# LEF file generated by Abstract Generator version 5.5.9 on Apr 28 16:11:38 2004
#
# Contains LEF for all bins.
# Options:   [ ] Antenna
#            [x] Geometry
#            [x] Technology

VERSION 5.7 ;
NAMESCASESENSITIVE ON ;
BUSBITCHARS "[]" ;
DIVIDERCHAR "/" ;

PROPERTYDEFINITIONS
  LAYER LEF57_SPACING STRING ;
  LAYER LEF57_ARRAYSPACING STRING ;
END PROPERTYDEFINITIONS

UNITS
  DATABASE MICRONS 1000 ;
END UNITS

USEMINSPACING OBS OFF ;
USEMINSPACING PIN OFF ;
CLEARANCEMEASURE EUCLIDEAN ;

MANUFACTURINGGRID 0.005 ;

LAYER DIFF
  TYPE MASTERSLICE ;
END DIFF

LAYER PO1
  TYPE MASTERSLICE ;
END PO1

LAYER VTPH
  TYPE IMPLANT ;
  SPACING 0.4  ;
  WIDTH 0.4 ;
END VTPH

LAYER VTNH
  TYPE IMPLANT ;
  SPACING 0.4  ;
  WIDTH 0.4 ;
END VTNH

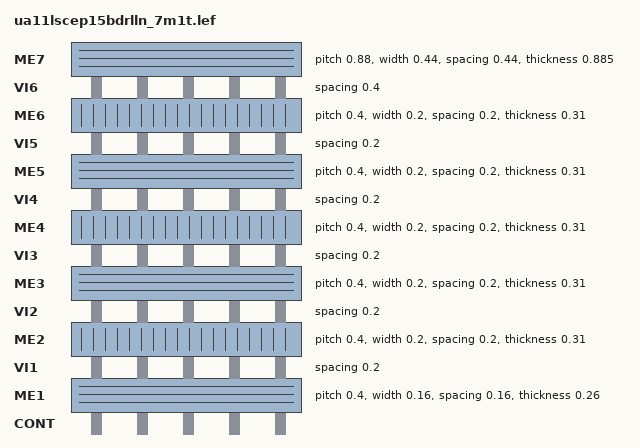
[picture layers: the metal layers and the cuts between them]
LAYER CONT
  TYPE CUT ;
END CONT

LAYER ME1
  TYPE		ROUTING ;
  DIRECTION	HORIZONTAL ;
  PITCH		0.4 ;
  OFFSET        0.2  ;
  WIDTH		0.16 ;
  SPACING	0.16 ;
  SPACING	0.22 RANGE 2.000 5.000  ;
  SPACING	0.26 RANGE 5.005 500  ;
  RESISTANCE	RPERSQ 0.196 ;
  CAPACITANCE	CPERSQDIST 1.7435e-04 ;
  EDGECAPACITANCE 1.0789e-04 ;
  THICKNESS 0.26 ;
  ANTENNASIDEAREARATIO 400 ;
  ANTENNADIFFSIDEAREARATIO PWL ( ( 0 400 ) ( 0.1023 400 ) ( 0.1024 2020 ) ( 100 22000 ) ) ;
  ANTENNACUMDIFFSIDEAREARATIO PWL ( ( 0 400 ) ( 0.1023 400 ) ( 0.1024 2020 ) ( 100 22000 ) ) ;
  AREA	0.1024 ;
  MINENCLOSEDAREA	0.3072 ;
  MINIMUMCUT	2 WIDTH	1.4 WITHIN 0.6 ;
  MINIMUMDENSITY 30 ;
  FILLACTIVESPACING  0.8 ;
END ME1

LAYER VI1
  TYPE	CUT ;
  SPACING    0.2 ;
  SPACING    0.24 ADJACENTCUTS 4 WITHIN 0.24 ;
END VI1

LAYER ME2
  TYPE		ROUTING ;
  DIRECTION	VERTICAL ;
  PITCH		0.4 ;
  OFFSET        0.2 ;  
  WIDTH		0.2 ;
  SPACING	0.2 ;
  SPACING	0.22 RANGE 2.000 5.000  ;
  SPACING	0.26 RANGE 5.005 500  ;
  RESISTANCE	RPERSQ 0.147 ;
  CAPACITANCE	CPERSQDIST 1.6801e-04 ;
  EDGECAPACITANCE 1.0243e-04 ;
  THICKNESS 0.31 ;
  ANTENNASIDEAREARATIO 400 ;
  ANTENNADIFFSIDEAREARATIO PWL ( ( 0 400 ) ( 0.1023 400 ) ( 0.1024 2020 ) ( 100 22000 ) ) ;
  ANTENNACUMDIFFSIDEAREARATIO PWL ( ( 0 400 ) ( 0.1023 400 ) ( 0.1024 2020 ) ( 100 22000 ) ) ;
  AREA	0.1024 ;
  MINENCLOSEDAREA	0.3072 ;
  MINIMUMCUT	2 WIDTH	1.4 WITHIN 0.6 ;
  MINIMUMDENSITY 30 ;
  FILLACTIVESPACING  0.8 ;  
END ME2

LAYER VI2
  TYPE	CUT ;
  SPACING    0.2 ;
  SPACING    0.24 ADJACENTCUTS 4 WITHIN 0.24 ;
END VI2

LAYER ME3
  TYPE		ROUTING ;
  DIRECTION	HORIZONTAL ;
  PITCH		0.4 ;
  OFFSET        0.2  ;  
  WIDTH		0.2 ;
  SPACING	0.2 ;
  SPACING	0.22 RANGE 2.000 5.000  ;
  SPACING	0.26 RANGE 5.005 500  ;
  RESISTANCE	RPERSQ 0.147 ;
  CAPACITANCE	CPERSQDIST 1.4924e-04 ;
  EDGECAPACITANCE 1.025e-04 ;
  THICKNESS 0.31 ;
  ANTENNASIDEAREARATIO 400 ;
  ANTENNADIFFSIDEAREARATIO PWL ( ( 0 400 ) ( 0.1023 400 ) ( 0.1024 2020 ) ( 100 22000 ) ) ;
  ANTENNACUMDIFFSIDEAREARATIO PWL ( ( 0 400 ) ( 0.1023 400 ) ( 0.1024 2020 ) ( 100 22000 ) ) ;
  AREA	0.1024 ;
  MINENCLOSEDAREA	0.3072 ;
  MINIMUMCUT	2 WIDTH	1.4 WITHIN 0.6 ;
  MINIMUMDENSITY 30 ;
  FILLACTIVESPACING  0.8 ;
END ME3

LAYER VI3
  TYPE	CUT ;
  SPACING    0.2 ;
  SPACING    0.24 ADJACENTCUTS 4 WITHIN 0.24 ;
END VI3

LAYER ME4
  TYPE		ROUTING ;
  DIRECTION	VERTICAL ;
  PITCH		0.4 ;
  OFFSET        0.2 ;  
  WIDTH		0.2 ;
  SPACING	0.2 ;
  SPACING	0.22 RANGE 2.000 5.000  ;
  SPACING	0.26 RANGE 5.005 500  ;
  RESISTANCE	RPERSQ 0.147 ;
  CAPACITANCE	CPERSQDIST 1.4924e-04 ;
  EDGECAPACITANCE 1.025e-04 ;
  THICKNESS 0.31 ;
  ANTENNASIDEAREARATIO 400 ;
  ANTENNADIFFSIDEAREARATIO PWL ( ( 0 400 ) ( 0.1023 400 ) ( 0.1024 2020 ) ( 100 22000 ) ) ;
  ANTENNACUMDIFFSIDEAREARATIO PWL ( ( 0 400 ) ( 0.1023 400 ) ( 0.1024 2020 ) ( 100 22000 ) ) ;
  AREA	0.1024 ;
  MINENCLOSEDAREA	0.3072 ;
  MINIMUMCUT	2 WIDTH	1.4 WITHIN 0.6 ;
  MINIMUMDENSITY 30 ;
  FILLACTIVESPACING  0.8 ;
END ME4

LAYER VI4
  TYPE	CUT ;
  SPACING    0.2 ;
  SPACING    0.24 ADJACENTCUTS 4 WITHIN 0.24 ;
END VI4

LAYER ME5
  TYPE		ROUTING ;
  DIRECTION	HORIZONTAL ;
  PITCH		0.4 ;
  OFFSET        0.2  ;
  WIDTH		0.2 ;
  SPACING	0.2 ;
  SPACING	0.22 RANGE 2.000 5.000  ;
  SPACING	0.26 RANGE 5.005 500  ;
  RESISTANCE	RPERSQ 0.147 ;
  CAPACITANCE	CPERSQDIST 1.4848e-04 ;
  EDGECAPACITANCE 1.025e-04 ;
  THICKNESS 0.31 ;
  ANTENNASIDEAREARATIO 400 ;
  ANTENNADIFFSIDEAREARATIO PWL ( ( 0 400 ) ( 0.1023 400 ) ( 0.1024 2020 ) ( 100 22000 ) ) ;
  ANTENNACUMDIFFSIDEAREARATIO PWL ( ( 0 400 ) ( 0.1023 400 ) ( 0.1024 2020 ) ( 100 22000 ) ) ;
  AREA	0.1024 ;
  MINENCLOSEDAREA	0.3072 ;
  MINIMUMCUT	2 WIDTH	1.4 WITHIN 0.6 ;
  MINIMUMDENSITY 30 ;
  FILLACTIVESPACING  0.8 ;  
END ME5

LAYER VI5
  TYPE	CUT ;
  SPACING    0.2 ;
  SPACING    0.24 ADJACENTCUTS 4 WITHIN 0.24 ;
END VI5

LAYER ME6
  TYPE		ROUTING ;
  DIRECTION	VERTICAL ;
  PITCH		0.4 ;
  OFFSET        0.2 ;  
  WIDTH		0.2 ;
  SPACING	0.2 ;
  SPACING	0.22 RANGE 2.000 5.000  ;
  SPACING	0.26 RANGE 5.005 500  ;
  RESISTANCE	RPERSQ 0.147 ;
  CAPACITANCE	CPERSQDIST 1.2056e-04 ;
  EDGECAPACITANCE 1.0259e-04 ;
  THICKNESS 0.31 ;
  ANTENNASIDEAREARATIO 400 ;
  ANTENNADIFFSIDEAREARATIO PWL ( ( 0 400 ) ( 0.1023 400 ) ( 0.1024 2020 ) ( 100 22000 ) ) ;
  ANTENNACUMDIFFSIDEAREARATIO PWL ( ( 0 400 ) ( 0.1023 400 ) ( 0.1024 2020 ) ( 100 22000 ) ) ;
  AREA	0.1024 ;
  MINENCLOSEDAREA	0.3072 ;
  MINIMUMCUT	2 WIDTH	1.4 WITHIN 0.6 ;
  MINIMUMDENSITY 30 ;
  FILLACTIVESPACING  0.8 ;  
END ME6

LAYER VI6
  TYPE	CUT ;
  SPACING    0.4 ;  
  SPACING    0.45 ADJACENTCUTS 4 WITHIN 0.5 ;
END VI6

LAYER ME7
  TYPE		ROUTING ;
  DIRECTION	HORIZONTAL ;
  PITCH		0.88 ;
  OFFSET        0.44 ;
  WIDTH		0.44 ;
  SPACING	0.44 ;
  SPACING	0.5 RANGE 2.000 500  ;
  RESISTANCE	RPERSQ 0.039 ;
  CAPACITANCE	CPERSQDIST 4.6793e-05 ;
  EDGECAPACITANCE 1.2087e-04 ;
  THICKNESS 0.885 ;
  ANTENNASIDEAREARATIO 400 ;
  ANTENNADIFFSIDEAREARATIO PWL ( ( 0 400 ) ( 0.1023 400 ) ( 0.1024 1520 ) ( 100 21500 ) ) ;
  ANTENNACUMDIFFSIDEAREARATIO PWL ( ( 0 400 ) ( 0.1023 400 ) ( 0.1024 2020 ) ( 100 22000 ) ) ;
  AREA	0.4075 ;
  MINENCLOSEDAREA	0.87 ;
  MINIMUMDENSITY 30 ;
  FILLACTIVESPACING  0.8 ;  
END ME7


VIA VIA12 DEFAULT
  LAYER ME1 ;
    RECT -0.160 -0.100 0.160 0.100 ;
  LAYER VI1 ;
    RECT -0.100 -0.100 0.100 0.100 ;
  LAYER ME2 ;
    RECT -0.100 -0.160 0.100 0.160 ;
  RESISTANCE 10 ;
END VIA12

VIA VIA23 DEFAULT
  LAYER ME2 ;
    RECT -0.100 -0.160 0.100 0.160 ;
  LAYER VI2 ;
    RECT -0.100 -0.100 0.100 0.100 ;
  LAYER ME3 ;
    RECT -0.160 -0.100 0.160 0.100 ;
  RESISTANCE 7 ;
END VIA23

VIA VIA34 DEFAULT
  LAYER ME3 ;
    RECT -0.160 -0.100 0.160 0.100 ;
  LAYER VI3 ;
    RECT -0.100 -0.100 0.100 0.100 ;
  LAYER ME4 ;
    RECT -0.100 -0.160 0.100 0.160 ;
  RESISTANCE 7 ;
END VIA34

VIA VIA45 DEFAULT
  LAYER ME4 ;
    RECT -0.100 -0.160 0.100 0.160 ;
  LAYER VI4 ;
    RECT -0.100 -0.100 0.100 0.100 ;
  LAYER ME5 ;
    RECT -0.160 -0.100 0.160 0.100 ;
  RESISTANCE 7 ;
END VIA45

VIA VIA56 DEFAULT
  LAYER ME5 ;
    RECT -0.160 -0.100 0.160 0.100 ;
  LAYER VI5 ;
    RECT -0.100 -0.100 0.100 0.100 ;
  LAYER ME6 ;
    RECT -0.100 -0.160 0.100 0.160 ;
  RESISTANCE 7 ;
END VIA56

VIA VIA67 DEFAULT
  LAYER ME6 ;
    RECT -0.200 -0.260 0.200 0.260 ;
  LAYER VI6 ;
    RECT -0.200 -0.200 0.200 0.200 ;
  LAYER ME7 ;
    RECT -0.260 -0.220 0.260 0.220 ;
  RESISTANCE 5.5 ;
END VIA67





# vias generated from signal via rules

VIA V12_VV DEFAULT 
    LAYER ME1 ; 
	RECT -0.100000 -0.160000 0.100000 0.160000 ;
    LAYER VI1 ; 
	RECT -0.100000 -0.100000 0.100000 0.100000 ;
    LAYER ME2 ; 
	RECT -0.100000 -0.160000 0.100000 0.160000 ;
    RESISTANCE 10.000000 ;
END V12_VV
VIA V12_VH DEFAULT 
    LAYER ME1 ; 
	RECT -0.100000 -0.160000 0.100000 0.160000 ;
    LAYER VI1 ; 
	RECT -0.100000 -0.100000 0.100000 0.100000 ;
    LAYER ME2 ; 
	RECT -0.160000 -0.100000 0.160000 0.100000 ;
    RESISTANCE 10.000000 ;
END V12_VH
VIA V12_HH DEFAULT 
    LAYER ME1 ; 
	RECT -0.160000 -0.100000 0.160000 0.100000 ;
    LAYER VI1 ; 
	RECT -0.100000 -0.100000 0.100000 0.100000 ;
    LAYER ME2 ; 
	RECT -0.160000 -0.100000 0.160000 0.100000 ;
    RESISTANCE 10.000000 ;
END V12_HH
VIA V12_2x1_HV_E DEFAULT 
    LAYER ME1 ; 
	RECT -0.160000 -0.100000 0.560000 0.100000 ;
    LAYER VI1 ; 
	RECT -0.100000 -0.100000 0.100000 0.100000 ;
	RECT 0.300000 -0.100000 0.500000 0.100000 ;
    LAYER ME2 ; 
	RECT -0.100000 -0.160000 0.500000 0.160000 ;
    RESISTANCE 5.000000 ;
END V12_2x1_HV_E
VIA V12_2x1_HV_W DEFAULT 
    LAYER ME1 ; 
	RECT -0.560000 -0.100000 0.160000 0.100000 ;
    LAYER VI1 ; 
	RECT -0.500000 -0.100000 -0.300000 0.100000 ;
	RECT -0.100000 -0.100000 0.100000 0.100000 ;
    LAYER ME2 ; 
	RECT -0.500000 -0.160000 0.100000 0.160000 ;
    RESISTANCE 5.000000 ;
END V12_2x1_HV_W
VIA V12_1x2_HV_N DEFAULT 
    LAYER ME1 ; 
	RECT -0.160000 -0.100000 0.160000 0.500000 ;
    LAYER VI1 ; 
	RECT -0.100000 -0.100000 0.100000 0.100000 ;
	RECT -0.100000 0.300000 0.100000 0.500000 ;
    LAYER ME2 ; 
	RECT -0.100000 -0.160000 0.100000 0.560000 ;
    RESISTANCE 5.000000 ;
END V12_1x2_HV_N
VIA V12_1x2_HV_S DEFAULT 
    LAYER ME1 ; 
	RECT -0.160000 -0.500000 0.160000 0.100000 ;
    LAYER VI1 ; 
	RECT -0.100000 -0.500000 0.100000 -0.300000 ;
	RECT -0.100000 -0.100000 0.100000 0.100000 ;
    LAYER ME2 ; 
	RECT -0.100000 -0.560000 0.100000 0.160000 ;
    RESISTANCE 5.000000 ;
END V12_1x2_HV_S
VIA V23_HH DEFAULT 
    LAYER ME2 ; 
	RECT -0.160000 -0.100000 0.160000 0.100000 ;
    LAYER VI2 ; 
	RECT -0.100000 -0.100000 0.100000 0.100000 ;
    LAYER ME3 ; 
	RECT -0.160000 -0.100000 0.160000 0.100000 ;
    RESISTANCE 7.000000 ;
END V23_HH
VIA V23_HV DEFAULT 
    LAYER ME2 ; 
	RECT -0.160000 -0.100000 0.160000 0.100000 ;
    LAYER VI2 ; 
	RECT -0.100000 -0.100000 0.100000 0.100000 ;
    LAYER ME3 ; 
	RECT -0.100000 -0.160000 0.100000 0.160000 ;
    RESISTANCE 7.000000 ;
END V23_HV
VIA V23_VV DEFAULT 
    LAYER ME2 ; 
	RECT -0.100000 -0.160000 0.100000 0.160000 ;
    LAYER VI2 ; 
	RECT -0.100000 -0.100000 0.100000 0.100000 ;
    LAYER ME3 ; 
	RECT -0.100000 -0.160000 0.100000 0.160000 ;
    RESISTANCE 7.000000 ;
END V23_VV
VIA V23_M_NH DEFAULT 
    LAYER ME2 ; 
	RECT -0.100000 -0.160000 0.100000 0.350000 ;
    LAYER VI2 ; 
	RECT -0.100000 -0.100000 0.100000 0.100000 ;
    LAYER ME3 ; 
	RECT -0.160000 -0.100000 0.160000 0.100000 ;
    RESISTANCE 7.000000 ;
END V23_M_NH
VIA V23_M_SH DEFAULT 
    LAYER ME2 ; 
	RECT -0.100000 -0.350000 0.100000 0.160000 ;
    LAYER VI2 ; 
	RECT -0.100000 -0.100000 0.100000 0.100000 ;
    LAYER ME3 ; 
	RECT -0.160000 -0.100000 0.160000 0.100000 ;
    RESISTANCE 7.000000 ;
END V23_M_SH
VIA V23_2x1_VH_E DEFAULT 
    LAYER ME2 ; 
	RECT -0.100000 -0.160000 0.500000 0.160000 ;
    LAYER VI2 ; 
	RECT -0.100000 -0.100000 0.100000 0.100000 ;
	RECT 0.300000 -0.100000 0.500000 0.100000 ;
    LAYER ME3 ; 
	RECT -0.160000 -0.100000 0.560000 0.100000 ;
    RESISTANCE 3.500000 ;
END V23_2x1_VH_E
VIA V23_2x1_VH_W DEFAULT 
    LAYER ME2 ; 
	RECT -0.500000 -0.160000 0.100000 0.160000 ;
    LAYER VI2 ; 
	RECT -0.500000 -0.100000 -0.300000 0.100000 ;
	RECT -0.100000 -0.100000 0.100000 0.100000 ;
    LAYER ME3 ; 
	RECT -0.560000 -0.100000 0.160000 0.100000 ;
    RESISTANCE 3.500000 ;
END V23_2x1_VH_W
VIA V23_1x2_VH_N DEFAULT 
    LAYER ME2 ; 
	RECT -0.100000 -0.160000 0.100000 0.560000 ;
    LAYER VI2 ; 
	RECT -0.100000 -0.100000 0.100000 0.100000 ;
	RECT -0.100000 0.300000 0.100000 0.500000 ;
    LAYER ME3 ; 
	RECT -0.160000 -0.100000 0.160000 0.500000 ;
    RESISTANCE 3.500000 ;
END V23_1x2_VH_N
VIA V23_1x2_VH_S DEFAULT 
    LAYER ME2 ; 
	RECT -0.100000 -0.560000 0.100000 0.160000 ;
    LAYER VI2 ; 
	RECT -0.100000 -0.500000 0.100000 -0.300000 ;
	RECT -0.100000 -0.100000 0.100000 0.100000 ;
    LAYER ME3 ; 
	RECT -0.160000 -0.500000 0.160000 0.100000 ;
    RESISTANCE 3.500000 ;
END V23_1x2_VH_S
VIA V34_VV DEFAULT 
    LAYER ME3 ; 
	RECT -0.100000 -0.160000 0.100000 0.160000 ;
    LAYER VI3 ; 
	RECT -0.100000 -0.100000 0.100000 0.100000 ;
    LAYER ME4 ; 
	RECT -0.100000 -0.160000 0.100000 0.160000 ;
    RESISTANCE 7.000000 ;
END V34_VV
VIA V34_VH DEFAULT 
    LAYER ME3 ; 
	RECT -0.100000 -0.160000 0.100000 0.160000 ;
    LAYER VI3 ; 
	RECT -0.100000 -0.100000 0.100000 0.100000 ;
    LAYER ME4 ; 
	RECT -0.160000 -0.100000 0.160000 0.100000 ;
    RESISTANCE 7.000000 ;
END V34_VH
VIA V34_HH DEFAULT 
    LAYER ME3 ; 
	RECT -0.160000 -0.100000 0.160000 0.100000 ;
    LAYER VI3 ; 
	RECT -0.100000 -0.100000 0.100000 0.100000 ;
    LAYER ME4 ; 
	RECT -0.160000 -0.100000 0.160000 0.100000 ;
    RESISTANCE 7.000000 ;
END V34_HH
VIA V34_M_EV DEFAULT 
    LAYER ME3 ; 
	RECT -0.160000 -0.100000 0.350000 0.100000 ;
    LAYER VI3 ; 
	RECT -0.100000 -0.100000 0.100000 0.100000 ;
    LAYER ME4 ; 
	RECT -0.100000 -0.160000 0.100000 0.160000 ;
    RESISTANCE 7.000000 ;
END V34_M_EV
VIA V34_M_WV DEFAULT 
    LAYER ME3 ; 
	RECT -0.350000 -0.100000 0.160000 0.100000 ;
    LAYER VI3 ; 
	RECT -0.100000 -0.100000 0.100000 0.100000 ;
    LAYER ME4 ; 
	RECT -0.100000 -0.160000 0.100000 0.160000 ;
    RESISTANCE 7.000000 ;
END V34_M_WV
VIA V34_2x1_HV_E DEFAULT 
    LAYER ME3 ; 
	RECT -0.160000 -0.100000 0.560000 0.100000 ;
    LAYER VI3 ; 
	RECT -0.100000 -0.100000 0.100000 0.100000 ;
	RECT 0.300000 -0.100000 0.500000 0.100000 ;
    LAYER ME4 ; 
	RECT -0.100000 -0.160000 0.500000 0.160000 ;
    RESISTANCE 3.500000 ;
END V34_2x1_HV_E
VIA V34_2x1_HV_W DEFAULT 
    LAYER ME3 ; 
	RECT -0.560000 -0.100000 0.160000 0.100000 ;
    LAYER VI3 ; 
	RECT -0.500000 -0.100000 -0.300000 0.100000 ;
	RECT -0.100000 -0.100000 0.100000 0.100000 ;
    LAYER ME4 ; 
	RECT -0.500000 -0.160000 0.100000 0.160000 ;
    RESISTANCE 3.500000 ;
END V34_2x1_HV_W
VIA V34_1x2_HV_N DEFAULT 
    LAYER ME3 ; 
	RECT -0.160000 -0.100000 0.160000 0.500000 ;
    LAYER VI3 ; 
	RECT -0.100000 -0.100000 0.100000 0.100000 ;
	RECT -0.100000 0.300000 0.100000 0.500000 ;
    LAYER ME4 ; 
	RECT -0.100000 -0.160000 0.100000 0.560000 ;
    RESISTANCE 3.500000 ;
END V34_1x2_HV_N
VIA V34_1x2_HV_S DEFAULT 
    LAYER ME3 ; 
	RECT -0.160000 -0.500000 0.160000 0.100000 ;
    LAYER VI3 ; 
	RECT -0.100000 -0.500000 0.100000 -0.300000 ;
	RECT -0.100000 -0.100000 0.100000 0.100000 ;
    LAYER ME4 ; 
	RECT -0.100000 -0.560000 0.100000 0.160000 ;
    RESISTANCE 3.500000 ;
END V34_1x2_HV_S
VIA V45_HH DEFAULT 
    LAYER ME4 ; 
	RECT -0.160000 -0.100000 0.160000 0.100000 ;
    LAYER VI4 ; 
	RECT -0.100000 -0.100000 0.100000 0.100000 ;
    LAYER ME5 ; 
	RECT -0.160000 -0.100000 0.160000 0.100000 ;
    RESISTANCE 7.000000 ;
END V45_HH
VIA V45_HV DEFAULT 
    LAYER ME4 ; 
	RECT -0.160000 -0.100000 0.160000 0.100000 ;
    LAYER VI4 ; 
	RECT -0.100000 -0.100000 0.100000 0.100000 ;
    LAYER ME5 ; 
	RECT -0.100000 -0.160000 0.100000 0.160000 ;
    RESISTANCE 7.000000 ;
END V45_HV
VIA V45_VV DEFAULT 
    LAYER ME4 ; 
	RECT -0.100000 -0.160000 0.100000 0.160000 ;
    LAYER VI4 ; 
	RECT -0.100000 -0.100000 0.100000 0.100000 ;
    LAYER ME5 ; 
	RECT -0.100000 -0.160000 0.100000 0.160000 ;
    RESISTANCE 7.000000 ;
END V45_VV
VIA V45_M_NH DEFAULT 
    LAYER ME4 ; 
	RECT -0.100000 -0.160000 0.100000 0.350000 ;
    LAYER VI4 ; 
	RECT -0.100000 -0.100000 0.100000 0.100000 ;
    LAYER ME5 ; 
	RECT -0.160000 -0.100000 0.160000 0.100000 ;
    RESISTANCE 7.000000 ;
END V45_M_NH
VIA V45_M_SH DEFAULT 
    LAYER ME4 ; 
	RECT -0.100000 -0.350000 0.100000 0.160000 ;
    LAYER VI4 ; 
	RECT -0.100000 -0.100000 0.100000 0.100000 ;
    LAYER ME5 ; 
	RECT -0.160000 -0.100000 0.160000 0.100000 ;
    RESISTANCE 7.000000 ;
END V45_M_SH
VIA V45_2x1_VH_E DEFAULT 
    LAYER ME4 ; 
	RECT -0.100000 -0.160000 0.500000 0.160000 ;
    LAYER VI4 ; 
	RECT -0.100000 -0.100000 0.100000 0.100000 ;
	RECT 0.300000 -0.100000 0.500000 0.100000 ;
    LAYER ME5 ; 
	RECT -0.160000 -0.100000 0.560000 0.100000 ;
    RESISTANCE 3.500000 ;
END V45_2x1_VH_E
VIA V45_2x1_VH_W DEFAULT 
    LAYER ME4 ; 
	RECT -0.500000 -0.160000 0.100000 0.160000 ;
    LAYER VI4 ; 
	RECT -0.500000 -0.100000 -0.300000 0.100000 ;
	RECT -0.100000 -0.100000 0.100000 0.100000 ;
    LAYER ME5 ; 
	RECT -0.560000 -0.100000 0.160000 0.100000 ;
    RESISTANCE 3.500000 ;
END V45_2x1_VH_W
VIA V45_1x2_VH_N DEFAULT 
    LAYER ME4 ; 
	RECT -0.100000 -0.160000 0.100000 0.560000 ;
    LAYER VI4 ; 
	RECT -0.100000 -0.100000 0.100000 0.100000 ;
	RECT -0.100000 0.300000 0.100000 0.500000 ;
    LAYER ME5 ; 
	RECT -0.160000 -0.100000 0.160000 0.500000 ;
    RESISTANCE 3.500000 ;
END V45_1x2_VH_N
VIA V45_1x2_VH_S DEFAULT 
    LAYER ME4 ; 
	RECT -0.100000 -0.560000 0.100000 0.160000 ;
    LAYER VI4 ; 
	RECT -0.100000 -0.500000 0.100000 -0.300000 ;
	RECT -0.100000 -0.100000 0.100000 0.100000 ;
    LAYER ME5 ; 
	RECT -0.160000 -0.500000 0.160000 0.100000 ;
    RESISTANCE 3.500000 ;
END V45_1x2_VH_S
VIA V56_VV DEFAULT 
    LAYER ME5 ; 
	RECT -0.100000 -0.160000 0.100000 0.160000 ;
    LAYER VI5 ; 
	RECT -0.100000 -0.100000 0.100000 0.100000 ;
    LAYER ME6 ; 
	RECT -0.100000 -0.160000 0.100000 0.160000 ;
    RESISTANCE 7.000000 ;
END V56_VV
VIA V56_VH DEFAULT 
    LAYER ME5 ; 
	RECT -0.100000 -0.160000 0.100000 0.160000 ;
    LAYER VI5 ; 
	RECT -0.100000 -0.100000 0.100000 0.100000 ;
    LAYER ME6 ; 
	RECT -0.160000 -0.100000 0.160000 0.100000 ;
    RESISTANCE 7.000000 ;
END V56_VH
VIA V56_HH DEFAULT 
    LAYER ME5 ; 
	RECT -0.160000 -0.100000 0.160000 0.100000 ;
    LAYER VI5 ; 
	RECT -0.100000 -0.100000 0.100000 0.100000 ;
    LAYER ME6 ; 
	RECT -0.160000 -0.100000 0.160000 0.100000 ;
    RESISTANCE 7.000000 ;
END V56_HH
VIA V56_M_EV DEFAULT 
    LAYER ME5 ; 
	RECT -0.160000 -0.100000 0.350000 0.100000 ;
    LAYER VI5 ; 
	RECT -0.100000 -0.100000 0.100000 0.100000 ;
    LAYER ME6 ; 
	RECT -0.100000 -0.160000 0.100000 0.160000 ;
    RESISTANCE 7.000000 ;
END V56_M_EV
VIA V56_M_WV DEFAULT 
    LAYER ME5 ; 
	RECT -0.350000 -0.100000 0.160000 0.100000 ;
    LAYER VI5 ; 
	RECT -0.100000 -0.100000 0.100000 0.100000 ;
    LAYER ME6 ; 
	RECT -0.100000 -0.160000 0.100000 0.160000 ;
    RESISTANCE 7.000000 ;
END V56_M_WV
VIA V56_2x1_HV_E DEFAULT 
    LAYER ME5 ; 
	RECT -0.160000 -0.100000 0.560000 0.100000 ;
    LAYER VI5 ; 
	RECT -0.100000 -0.100000 0.100000 0.100000 ;
	RECT 0.300000 -0.100000 0.500000 0.100000 ;
    LAYER ME6 ; 
	RECT -0.100000 -0.160000 0.500000 0.160000 ;
    RESISTANCE 3.500000 ;
END V56_2x1_HV_E
VIA V56_2x1_HV_W DEFAULT 
    LAYER ME5 ; 
	RECT -0.560000 -0.100000 0.160000 0.100000 ;
    LAYER VI5 ; 
	RECT -0.500000 -0.100000 -0.300000 0.100000 ;
	RECT -0.100000 -0.100000 0.100000 0.100000 ;
    LAYER ME6 ; 
	RECT -0.500000 -0.160000 0.100000 0.160000 ;
    RESISTANCE 3.500000 ;
END V56_2x1_HV_W
VIA V56_1x2_HV_N DEFAULT 
    LAYER ME5 ; 
	RECT -0.160000 -0.100000 0.160000 0.500000 ;
    LAYER VI5 ; 
	RECT -0.100000 -0.100000 0.100000 0.100000 ;
	RECT -0.100000 0.300000 0.100000 0.500000 ;
    LAYER ME6 ; 
	RECT -0.100000 -0.160000 0.100000 0.560000 ;
    RESISTANCE 3.500000 ;
END V56_1x2_HV_N
VIA V56_1x2_HV_S DEFAULT 
    LAYER ME5 ; 
	RECT -0.160000 -0.500000 0.160000 0.100000 ;
    LAYER VI5 ; 
	RECT -0.100000 -0.500000 0.100000 -0.300000 ;
	RECT -0.100000 -0.100000 0.100000 0.100000 ;
    LAYER ME6 ; 
	RECT -0.100000 -0.560000 0.100000 0.160000 ;
    RESISTANCE 3.500000 ;
END V56_1x2_HV_S
VIA V67_HH DEFAULT 
    LAYER ME6 ; 
	RECT -0.260000 -0.200000 0.260000 0.200000 ;
    LAYER VI6 ; 
	RECT -0.200000 -0.200000 0.200000 0.200000 ;
    LAYER ME7 ; 
	RECT -0.260000 -0.220000 0.260000 0.220000 ;
    RESISTANCE 5.500000 ;
END V67_HH
VIA V67_HV DEFAULT 
    LAYER ME6 ; 
	RECT -0.260000 -0.200000 0.260000 0.200000 ;
    LAYER VI6 ; 
	RECT -0.200000 -0.200000 0.200000 0.200000 ;
    LAYER ME7 ; 
	RECT -0.220000 -0.260000 0.220000 0.260000 ;
    RESISTANCE 5.500000 ;
END V67_HV
VIA V67_VV DEFAULT 
    LAYER ME6 ; 
	RECT -0.200000 -0.260000 0.200000 0.260000 ;
    LAYER VI6 ; 
	RECT -0.200000 -0.200000 0.200000 0.200000 ;
    LAYER ME7 ; 
	RECT -0.220000 -0.260000 0.220000 0.260000 ;
    RESISTANCE 5.500000 ;
END V67_VV
VIA V67_2x1_VH_E DEFAULT 
    LAYER ME6 ; 
	RECT -0.200000 -0.260000 1.000000 0.260000 ;
    LAYER VI6 ; 
	RECT -0.200000 -0.200000 0.200000 0.200000 ;
	RECT 0.600000 -0.200000 1.000000 0.200000 ;
    LAYER ME7 ; 
	RECT -0.260000 -0.220000 1.060000 0.220000 ;
    RESISTANCE 2.750000 ;
END V67_2x1_VH_E
VIA V67_2x1_VH_W DEFAULT 
    LAYER ME6 ; 
	RECT -1.000000 -0.260000 0.200000 0.260000 ;
    LAYER VI6 ; 
	RECT -1.000000 -0.200000 -0.600000 0.200000 ;
	RECT -0.200000 -0.200000 0.200000 0.200000 ;
    LAYER ME7 ; 
	RECT -1.060000 -0.220000 0.260000 0.220000 ;
    RESISTANCE 2.750000 ;
END V67_2x1_VH_W
VIA V67_1x2_VH_N DEFAULT 
    LAYER ME6 ; 
	RECT -0.200000 -0.260000 0.200000 1.060000 ;
    LAYER VI6 ; 
	RECT -0.200000 -0.200000 0.200000 0.200000 ;
	RECT -0.200000 0.600000 0.200000 1.000000 ;
    LAYER ME7 ; 
	RECT -0.260000 -0.220000 0.260000 1.020000 ;
    RESISTANCE 2.750000 ;
END V67_1x2_VH_N
VIA V67_1x2_VH_S DEFAULT 
    LAYER ME6 ; 
	RECT -0.200000 -1.060000 0.200000 0.260000 ;
    LAYER VI6 ; 
	RECT -0.200000 -1.000000 0.200000 -0.600000 ;
	RECT -0.200000 -0.200000 0.200000 0.200000 ;
    LAYER ME7 ; 
	RECT -0.260000 -1.020000 0.260000 0.220000 ;
    RESISTANCE 2.750000 ;
END V67_1x2_VH_S

# end auto generated vias

VIARULE genm1m2 GENERATE
  LAYER ME1 ;
    ENCLOSURE 0.06 0 ;
    WIDTH 0.16 TO 9.99 ;
  LAYER ME2 ;
    ENCLOSURE 0.06 0 ;
    WIDTH 0.20 TO 9.99 ;
  LAYER VI1 ;
    RECT -0.100 -0.100 0.100 0.100 ;
    SPACING 0.44 BY 0.44 ;
END genm1m2

VIARULE genm1m2_wide GENERATE
  LAYER ME1 ;
    ENCLOSURE 0.18 0.06 ;
    WIDTH 10 TO 999 ;
  LAYER ME2 ;
    ENCLOSURE 0.06 0 ;
    WIDTH 10 TO 999 ;
  LAYER VI1 ;
    RECT -0.100 -0.100 0.100 0.100 ;
    SPACING 0.44 BY 0.44 ;
END genm1m2_wide

VIARULE genm2m3 GENERATE
  LAYER ME2 ;
    ENCLOSURE 0.06 0 ;
    WIDTH 0.20 TO 9.99 ;
  LAYER ME3 ;
    ENCLOSURE 0.06 0 ;
    WIDTH 0.20 TO 9.99 ;
  LAYER VI2 ;
    RECT -0.100 -0.100 0.100 0.100 ;
    SPACING 0.44 BY 0.44 ;
END genm2m3

VIARULE genm2m3_wide GENERATE
  LAYER ME2 ;
    ENCLOSURE 0.18 0.06 ;
    WIDTH 10 TO 999 ;
  LAYER ME3 ;
    ENCLOSURE 0.06 0 ;
    WIDTH 10 TO 999 ;
  LAYER VI2 ;
    RECT -0.100 -0.100 0.100 0.100 ;
    SPACING 0.44 BY 0.44 ;
END genm2m3_wide

VIARULE genm3m4 GENERATE
  LAYER ME3 ;
    ENCLOSURE 0.06 0 ;
    WIDTH 0.20 TO 9.99 ;
  LAYER ME4 ;
    ENCLOSURE 0.06 0 ;
    WIDTH 0.20 TO 9.99 ;
  LAYER VI3 ;
    RECT -0.100 -0.100 0.100 0.100 ;
    SPACING 0.44 BY 0.44 ;
END genm3m4

VIARULE genm3m4_wide GENERATE
  LAYER ME3 ;
    ENCLOSURE 0.18 0.06 ;
    WIDTH 10 TO 999 ;
  LAYER ME4 ;
    ENCLOSURE 0.06 0 ;
    WIDTH 10 TO 999 ;
  LAYER VI3 ;
    RECT -0.100 -0.100 0.100 0.100 ;
    SPACING 0.44 BY 0.44 ;
END genm3m4_wide

VIARULE genm4m5 GENERATE
  LAYER ME4 ;
    ENCLOSURE 0.06 0 ;
    WIDTH 0.20 TO 9.99 ;
  LAYER ME5 ;
    ENCLOSURE 0.06 0 ;
    WIDTH 0.20 TO 9.99 ;
  LAYER VI4 ;
    RECT -0.100 -0.100 0.100 0.100 ;
    SPACING 0.44 BY 0.44 ;
END genm4m5

VIARULE genm4m5_wide GENERATE
  LAYER ME4 ;
    ENCLOSURE 0.18 0.06 ;
    WIDTH 10 TO 999 ;
  LAYER ME5 ;
    ENCLOSURE 0.06 0 ;
    WIDTH 10 TO 999 ;
  LAYER VI4 ;
    RECT -0.100 -0.100 0.100 0.100 ;
    SPACING 0.44 BY 0.44 ;
END genm4m5_wide

VIARULE genm5m6 GENERATE
  LAYER ME5 ;
    ENCLOSURE 0.06 0 ;
    WIDTH 0.20 TO 9.99 ;
  LAYER ME6 ;
    ENCLOSURE 0.06 0 ;
    WIDTH 0.20 TO 9.99 ;
  LAYER VI5 ;
    RECT -0.100 -0.100 0.100 0.100 ;
    SPACING 0.44 BY 0.44 ;
END genm5m6

VIARULE genm5m6_wide GENERATE
  LAYER ME5 ;
    ENCLOSURE 0.18 0.06 ;
    WIDTH 10 TO 999 ;
  LAYER ME6 ;
    ENCLOSURE 0.06 0 ;
    WIDTH 10 TO 999 ;
  LAYER VI5 ;
    RECT -0.100 -0.100 0.100 0.100 ;
    SPACING 0.44 BY 0.44 ;
END genm5m6_wide

VIARULE genm6m7 GENERATE
  LAYER ME6 ;
    ENCLOSURE 0.06 0 ;
    WIDTH 0.20 TO 9.99 ;
  LAYER ME7 ;
    ENCLOSURE 0.06 0 ;
    WIDTH 0.44 TO 9.99 ;
  LAYER VI6 ;
    RECT -0.200 -0.200 0.200 0.200 ;
    SPACING 0.85 BY 0.85 ;
END genm6m7

VIARULE genm6m7_wide GENERATE
  LAYER ME6 ;
    ENCLOSURE 0.18 0.06 ;
    WIDTH 10 TO 999 ;
  LAYER ME7 ;
    ENCLOSURE 0.06 0 ;
    WIDTH 10 TO 999 ;
  LAYER VI6 ;
    RECT -0.200 -0.200 0.200 0.200 ;
    SPACING 0.85 BY 0.85 ;
END genm6m7_wide


SPACING
  SAMENET ME1  ME1	0.160  STACK ;
  SAMENET ME2  ME2	0.200  STACK ;
  SAMENET ME3  ME3	0.200  STACK ;
  SAMENET ME4  ME4	0.200  STACK ;
  SAMENET ME5  ME5	0.200  STACK ;
  SAMENET ME6  ME6	0.200  STACK ;
  SAMENET ME7  ME7	0.440  STACK ;
  SAMENET VI1  VI1	0.200 ;
  SAMENET VI2  VI2	0.200 ;
  SAMENET VI3  VI3	0.200 ;
  SAMENET VI4  VI4	0.200 ;
  SAMENET VI5  VI5	0.200 ;
  SAMENET VI6  VI6	0.400 ;
  SAMENET CONT  VI1	0.000  STACK ;
  SAMENET VI1  VI2	0.000  STACK ;
  SAMENET VI2  VI3	0.000  STACK ;
  SAMENET VI3  VI4	0.000  STACK ;
  SAMENET VI4  VI5	0.000  STACK ;
  SAMENET VI5  VI6	0.000  STACK ;
END SPACING

SITE CORE_6T
    SYMMETRY Y  ;
    CLASS core  ;
    SIZE 0.40 BY 2.40 ;
END CORE_6T


END LIBRARY
